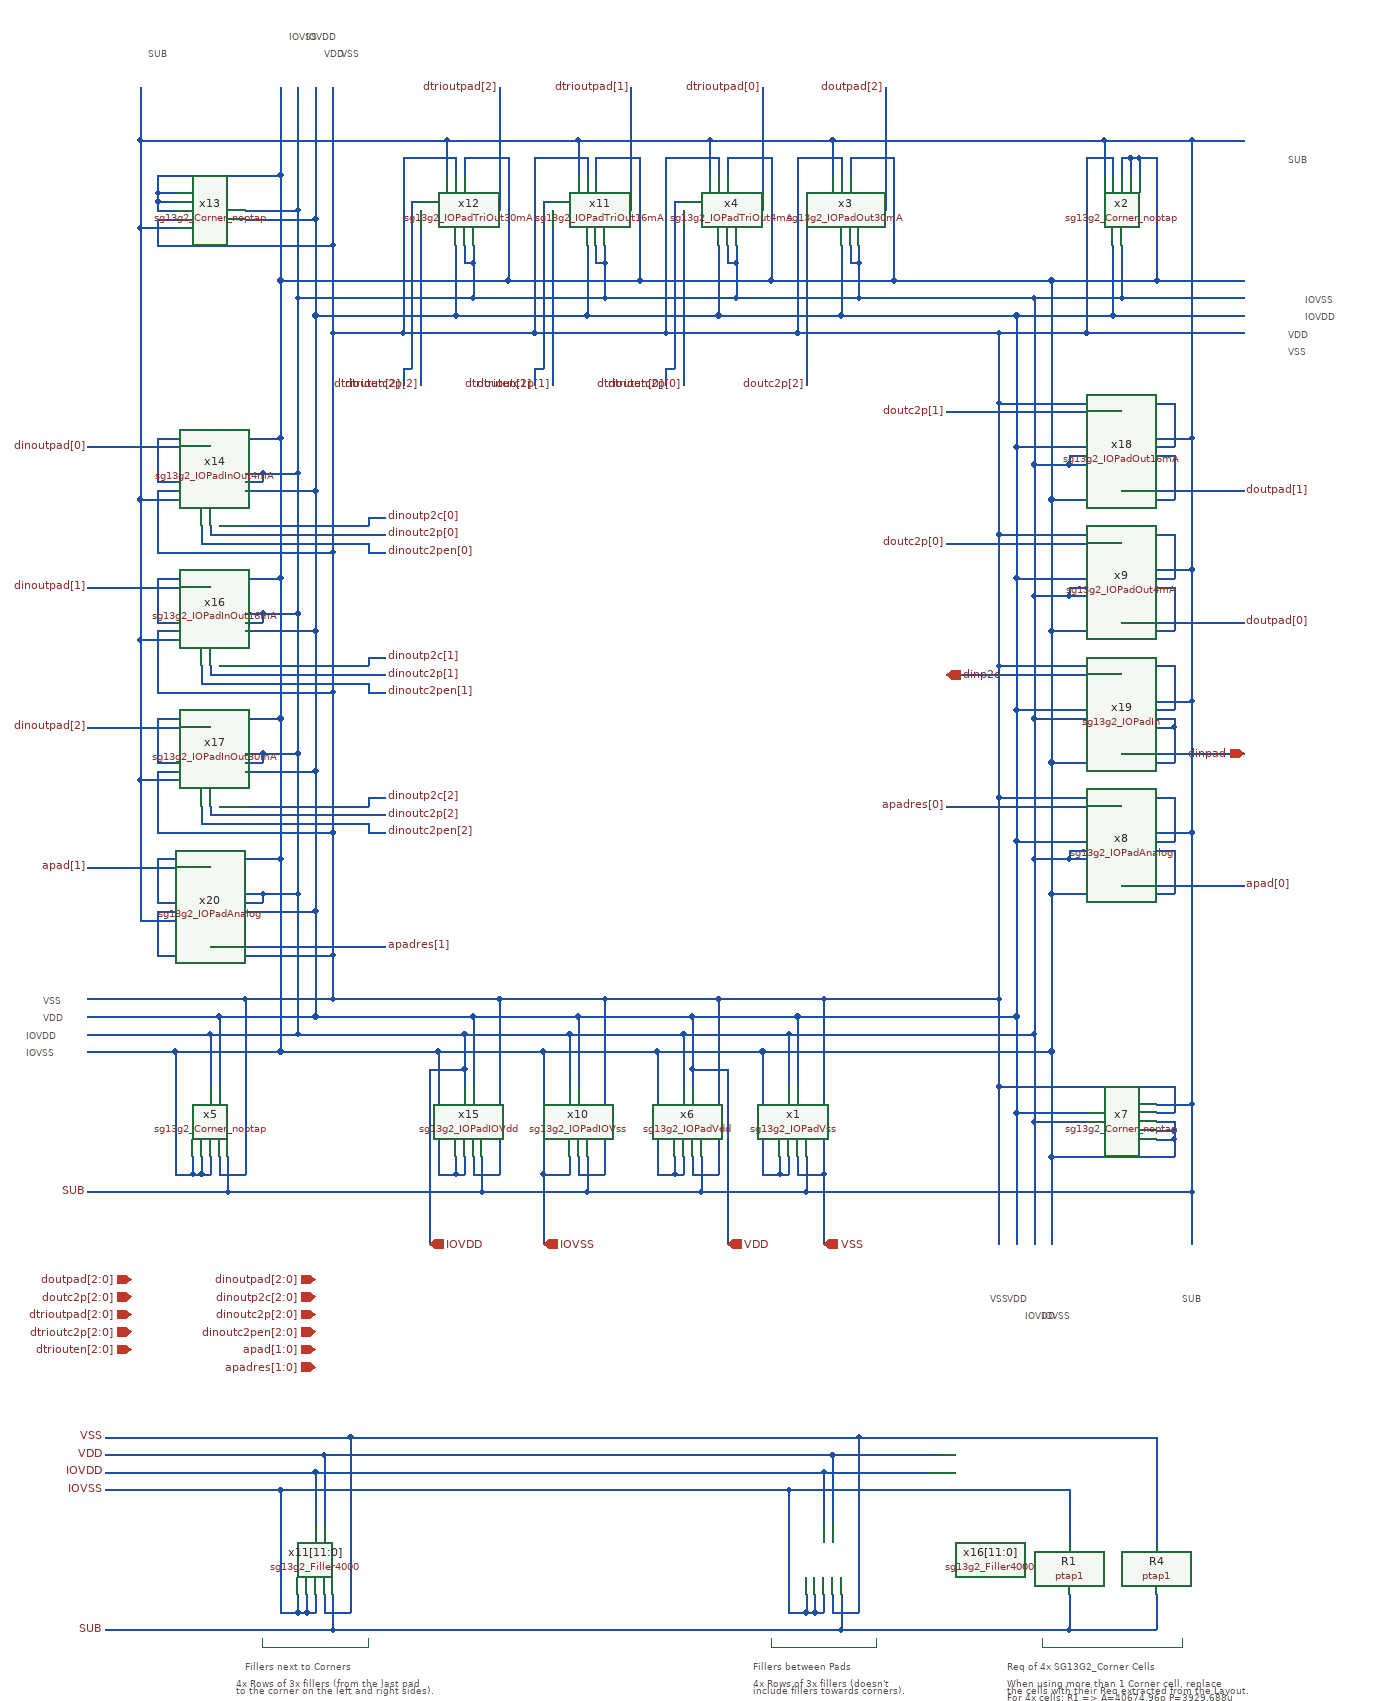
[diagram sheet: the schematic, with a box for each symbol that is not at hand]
v {xschem version=3.4.6 file_version=1.2}
G {}
K {}
V {}
S {}
E {}
L 4 1230 430 1230 440 {}
L 4 1230 440 1390 440 {}
L 4 1390 430 1390 440 {}
L 4 920 430 920 440 {}
L 4 920 440 1040 440 {}
L 4 1040 430 1040 440 {}
L 4 340 430 340 440 {}
L 4 340 440 460 440 {}
L 4 460 430 460 440 {}
T {VSS} 1170 30 3 0 0.3 0.3 {}
T {VDD} 1190 30 3 0 0.3 0.3 {}
T {IOVDD} 1210 50 3 0 0.3 0.3 {}
T {IOVSS} 1230 50 3 0 0.3 0.3 {}
T {SUB} 1390 30 3 0 0.3 0.3 {}
T {Req of 4x SG13G2_Corner Cells} 1190 450 0 0 0.3 0.3 {}
T {When using more than 1 Corner cell, replace
the cells with their Req extracted from the Layout.
For 4x cells: R1 => A=40674.96p P=3929.688u
              R2 => A=52.7736p P=338.816u} 1190 470 0 0 0.2 0.2 {}
T {Fillers between Pads} 900 450 0 0 0.3 0.3 {}
T {4x Rows of 3x fillers (doesn't
include fillers towards corners).} 900 470 0 0 0.2 0.2 {}
T {Fillers next to Corners} 320 450 0 0 0.3 0.3 {}
T {4x Rows of 3x fillers (from the last pad
to the corner on the left and right sides).} 310 470 0 0 0.2 0.2 {}
T {VSS} 1510 -1050 2 0 0.3 0.3 {}
T {VDD} 1510 -1070 2 0 0.3 0.3 {}
T {IOVDD} 1530 -1090 2 0 0.3 0.3 {}
T {IOVSS} 1530 -1110 2 0 0.3 0.3 {}
T {SUB} 1510 -1270 2 0 0.3 0.3 {}
T {VSS} 430 -1390 1 0 0.3 0.3 {}
T {VDD} 410 -1390 1 0 0.3 0.3 {}
T {IOVDD} 390 -1410 1 0 0.3 0.3 {}
T {IOVSS} 370 -1410 1 0 0.3 0.3 {}
T {SUB} 210 -1390 1 0 0.3 0.3 {}
T {VSS} 90 -310 0 0 0.3 0.3 {}
T {VDD} 90 -290 0 0 0.3 0.3 {}
T {IOVDD} 70 -270 0 0 0.3 0.3 {}
T {IOVSS} 70 -250 0 0 0.3 0.3 {}
N 140 -300 320 -300 {lab=VSS}
N 140 -280 290 -280 {lab=VDD}
N 140 -260 280 -260 {lab=IOVDD}
N 140 -240 240 -240 {lab=IOVSS}
N 300 -120 300 -80 {lab=SUB}
N 260 -120 260 -100 {lab=IOVSS}
N 270 -120 270 -100 {lab=IOVSS}
N 260 -100 270 -100 {lab=IOVSS}
N 290 -120 290 -100 {lab=VSS}
N 290 -100 320 -100 {lab=VSS}
N 320 -300 320 -100 {lab=VSS}
N 290 -280 290 -200 {lab=VDD}
N 280 -260 280 -200 {lab=IOVDD}
N 240 -100 260 -100 {lab=IOVSS}
N 240 -240 240 -100 {lab=IOVSS}
N 280 -120 280 -100 {lab=IOVSS}
N 270 -100 280 -100 {lab=IOVSS}
N 580 -120 580 -100 {lab=VSS}
N 580 -100 610 -100 {lab=VSS}
N 610 -300 610 -100 {lab=VSS}
N 580 -280 580 -200 {lab=VDD}
N 570 -220 570 -200 {lab=IOVDD}
N 560 -120 560 -100 {lab=IOVSS}
N 570 -120 570 -100 {lab=IOVSS}
N 560 -100 570 -100 {lab=IOVSS}
N 540 -100 560 -100 {lab=IOVSS}
N 540 -240 540 -100 {lab=IOVSS}
N 700 -120 700 -100 {lab=VSS}
N 700 -100 730 -100 {lab=VSS}
N 730 -300 730 -100 {lab=VSS}
N 700 -280 700 -200 {lab=VDD}
N 690 -260 690 -200 {lab=IOVDD}
N 690 -120 690 -100 {lab=IOVSS}
N 660 -100 690 -100 {lab=IOVSS}
N 660 -240 660 -100 {lab=IOVSS}
N 610 -300 730 -300 {lab=VSS}
N 580 -280 700 -280 {lab=VDD}
N 570 -260 690 -260 {lab=IOVDD}
N 540 -240 660 -240 {lab=IOVSS}
N 910 -240 1240 -240 {lab=IOVSS}
N 980 -300 1180 -300 {lab=VSS}
N 940 -260 1220 -260 {lab=IOVDD}
N 160 200 440 200 {lab=VSS}
N 160 220 410 220 {lab=VDD}
N 160 240 400 240 {lab=IOVDD}
N 160 260 360 260 {lab=IOVSS}
N 160 420 420 420 {lab=SUB}
N 420 380 420 420 {lab=SUB}
N 380 380 380 400 {lab=IOVSS}
N 390 380 390 400 {lab=IOVSS}
N 380 400 390 400 {lab=IOVSS}
N 410 380 410 400 {lab=VSS}
N 410 400 440 400 {lab=VSS}
N 440 200 440 400 {lab=VSS}
N 410 220 410 300 {lab=VDD}
N 400 240 400 300 {lab=IOVDD}
N 360 400 380 400 {lab=IOVSS}
N 360 260 360 400 {lab=IOVSS}
N 400 380 400 400 {lab=IOVSS}
N 390 400 400 400 {lab=IOVSS}
N 440 200 1020 200 {lab=VSS}
N 410 220 990 220 {lab=VDD}
N 400 240 980 240 {lab=IOVDD}
N 360 260 940 260 {lab=IOVSS}
N 960 380 960 400 {lab=IOVSS}
N 970 380 970 400 {lab=IOVSS}
N 960 400 970 400 {lab=IOVSS}
N 990 380 990 400 {lab=VSS}
N 990 400 1020 400 {lab=VSS}
N 1020 200 1020 400 {lab=VSS}
N 990 220 990 300 {lab=VDD}
N 980 240 980 300 {lab=IOVDD}
N 940 400 960 400 {lab=IOVSS}
N 940 260 940 400 {lab=IOVSS}
N 980 380 980 400 {lab=IOVSS}
N 970 400 980 400 {lab=IOVSS}
N 1020 200 1360 200 {lab=VSS}
N 990 220 1110 220 {lab=VDD}
N 980 240 1100 240 {lab=IOVDD}
N 940 260 1260 260 {lab=IOVSS}
N 1000 420 1260 420 {lab=SUB}
N 1000 380 1000 420 {lab=SUB}
N 420 420 1000 420 {lab=SUB}
N 710 -120 710 -80 {lab=SUB}
N 590 -80 710 -80 {lab=SUB}
N 590 -120 590 -80 {lab=SUB}
N 300 -80 590 -80 {lab=SUB}
N 1200 -170 1200 -20 {lab=VDD}
N 1220 -160 1220 -20 {lab=IOVDD}
N 1240 -120 1240 -20 {lab=IOVSS}
N 1360 -180 1400 -180 {lab=SUB}
N 1360 -140 1380 -140 {lab=IOVSS}
N 1360 -150 1380 -150 {lab=IOVSS}
N 1380 -150 1380 -140 {lab=IOVSS}
N 1360 -170 1380 -170 {lab=VSS}
N 1380 -200 1380 -170 {lab=VSS}
N 1180 -200 1380 -200 {lab=VSS}
N 1200 -170 1280 -170 {lab=VDD}
N 1220 -160 1280 -160 {lab=IOVDD}
N 1380 -140 1380 -120 {lab=IOVSS}
N 1240 -120 1380 -120 {lab=IOVSS}
N 1360 -160 1380 -160 {lab=IOVSS}
N 1380 -160 1380 -150 {lab=IOVSS}
N 1180 -300 1180 -200 {lab=VSS}
N 1200 -280 1200 -170 {lab=VDD}
N 1220 -260 1220 -160 {lab=IOVDD}
N 1240 -240 1240 -120 {lab=IOVSS}
N 1120 -520 1320 -520 {lab=apadres[0]}
N 1320 -430 1460 -430 {lab=apad[0]}
N 1360 -470 1380 -470 {lab=IOVSS}
N 1380 -470 1380 -420 {lab=IOVSS}
N 1240 -420 1380 -420 {lab=IOVSS}
N 1240 -420 1240 -240 {lab=IOVSS}
N 1360 -480 1380 -480 {lab=VSS}
N 1380 -530 1380 -480 {lab=VSS}
N 1180 -530 1380 -530 {lab=VSS}
N 1180 -530 1180 -300 {lab=VSS}
N 1260 -460 1280 -460 {lab=IOVDD}
N 1220 -460 1220 -260 {lab=IOVDD}
N 1260 -470 1280 -470 {lab=IOVDD}
N 1260 -470 1260 -460 {lab=IOVDD}
N 1220 -460 1260 -460 {lab=IOVDD}
N 1200 -480 1280 -480 {lab=VDD}
N 1200 -480 1200 -280 {lab=VDD}
N 1120 -670 1320 -670 {lab=dinp2c}
N 1320 -580 1460 -580 {lab=dinpad}
N 1360 -620 1380 -620 {lab=IOVSS}
N 1380 -610 1380 -570 {lab=IOVSS}
N 1240 -570 1380 -570 {lab=IOVSS}
N 1360 -630 1380 -630 {lab=VSS}
N 1380 -680 1380 -630 {lab=VSS}
N 1180 -680 1380 -680 {lab=VSS}
N 1200 -630 1280 -630 {lab=VDD}
N 1240 -570 1240 -420 {lab=IOVSS}
N 1180 -680 1180 -530 {lab=VSS}
N 1200 -630 1200 -480 {lab=VDD}
N 1360 -640 1400 -640 {lab=SUB}
N 1400 -640 1400 -490 {lab=SUB}
N 1360 -490 1400 -490 {lab=SUB}
N 1400 -490 1400 -180 {lab=SUB}
N 1400 -80 1400 -20 {lab=SUB}
N 1260 260 1260 320 {lab=IOVSS}
N 1260 380 1260 420 {lab=SUB}
N 1260 420 1360 420 {lab=SUB}
N 1360 380 1360 420 {lab=SUB}
N 1360 200 1360 320 {lab=VSS}
N 1180 -200 1180 -20 {lab=VSS}
N 1310 -1080 1460 -1080 {lab=VDD}
N 1320 -1100 1460 -1100 {lab=IOVDD}
N 1360 -1120 1460 -1120 {lab=IOVSS}
N 1300 -1280 1300 -1240 {lab=SUB}
N 1340 -1260 1340 -1240 {lab=IOVSS}
N 1330 -1260 1330 -1240 {lab=IOVSS}
N 1330 -1260 1340 -1260 {lab=IOVSS}
N 1310 -1260 1310 -1240 {lab=VSS}
N 1280 -1260 1310 -1260 {lab=VSS}
N 1280 -1260 1280 -1060 {lab=VSS}
N 1310 -1160 1310 -1080 {lab=VDD}
N 1320 -1160 1320 -1100 {lab=IOVDD}
N 1340 -1260 1360 -1260 {lab=IOVSS}
N 1360 -1260 1360 -1120 {lab=IOVSS}
N 1320 -1260 1320 -1240 {lab=IOVSS}
N 1320 -1260 1330 -1260 {lab=IOVSS}
N 1180 -1060 1280 -1060 {lab=VSS}
N 1200 -1080 1310 -1080 {lab=VDD}
N 1220 -1100 1320 -1100 {lab=IOVDD}
N 1240 -1120 1360 -1120 {lab=IOVSS}
N 1400 -1280 1460 -1280 {lab=SUB}
N 1280 -1060 1460 -1060 {lab=VSS}
N 1400 -180 1400 -80 {lab=SUB}
N 1400 -790 1400 -640 {lab=SUB}
N 1300 -1280 1400 -1280 {lab=SUB}
N 1180 -830 1180 -680 {lab=VSS}
N 1220 -620 1220 -460 {lab=IOVDD}
N 1240 -720 1240 -570 {lab=IOVSS}
N 1060 -1120 1240 -1120 {lab=IOVSS}
N 400 -1340 400 -1190 {lab=VDD}
N 380 -1340 380 -1200 {lab=IOVDD}
N 360 -1340 360 -1240 {lab=IOVSS}
N 200 -1180 240 -1180 {lab=SUB}
N 220 -1220 240 -1220 {lab=IOVSS}
N 220 -1210 240 -1210 {lab=IOVSS}
N 220 -1220 220 -1210 {lab=IOVSS}
N 220 -1190 240 -1190 {lab=VSS}
N 220 -1190 220 -1160 {lab=VSS}
N 220 -1160 420 -1160 {lab=VSS}
N 320 -1190 400 -1190 {lab=VDD}
N 320 -1200 380 -1200 {lab=IOVDD}
N 220 -1240 220 -1220 {lab=IOVSS}
N 220 -1240 360 -1240 {lab=IOVSS}
N 220 -1200 240 -1200 {lab=IOVSS}
N 220 -1210 220 -1200 {lab=IOVSS}
N 420 -1340 420 -1160 {lab=VSS}
N 200 -1280 200 -1180 {lab=SUB}
N 360 -460 360 -240 {lab=IOVSS}
N 380 -420 380 -260 {lab=IOVDD}
N 400 -400 400 -280 {lab=VDD}
N 140 -80 300 -80 {lab=SUB}
N 420 -300 610 -300 {lab=VSS}
N 400 -280 580 -280 {lab=VDD}
N 380 -260 570 -260 {lab=IOVDD}
N 360 -240 540 -240 {lab=IOVSS}
N 530 -220 570 -220 {lab=IOVDD}
N 570 -260 570 -220 {lab=IOVDD}
N 530 -220 530 -20 {lab=IOVDD}
N 660 -100 660 -20 {lab=IOVSS}
N 950 -280 1200 -280 {lab=VDD}
N 960 -80 1400 -80 {lab=SUB}
N 830 -120 830 -100 {lab=VSS}
N 830 -100 860 -100 {lab=VSS}
N 860 -300 860 -100 {lab=VSS}
N 830 -220 830 -200 {lab=VDD}
N 810 -120 810 -100 {lab=IOVSS}
N 820 -120 820 -100 {lab=IOVSS}
N 810 -100 820 -100 {lab=IOVSS}
N 790 -100 810 -100 {lab=IOVSS}
N 790 -240 790 -100 {lab=IOVSS}
N 950 -120 950 -100 {lab=VSS}
N 950 -100 980 -100 {lab=VSS}
N 980 -300 980 -100 {lab=VSS}
N 950 -280 950 -200 {lab=VDD}
N 940 -260 940 -200 {lab=IOVDD}
N 940 -120 940 -100 {lab=IOVSS}
N 930 -100 940 -100 {lab=IOVSS}
N 910 -240 910 -100 {lab=IOVSS}
N 960 -120 960 -80 {lab=SUB}
N 840 -120 840 -80 {lab=SUB}
N 820 -260 820 -200 {lab=IOVDD}
N 730 -300 860 -300 {lab=VSS}
N 700 -280 830 -280 {lab=VDD}
N 660 -240 790 -240 {lab=IOVSS}
N 860 -300 980 -300 {lab=VSS}
N 830 -280 950 -280 {lab=VDD}
N 820 -260 940 -260 {lab=IOVDD}
N 790 -240 910 -240 {lab=IOVSS}
N 840 -80 960 -80 {lab=SUB}
N 710 -80 840 -80 {lab=SUB}
N 690 -260 820 -260 {lab=IOVDD}
N 830 -220 870 -220 {lab=VDD}
N 830 -280 830 -220 {lab=VDD}
N 870 -220 870 -20 {lab=VDD}
N 980 -100 980 -20 {lab=VSS}
N 1220 -620 1280 -620 {lab=IOVDD}
N 1220 -760 1220 -620 {lab=IOVDD}
N 1360 -610 1380 -610 {lab=IOVSS}
N 1380 -620 1380 -610 {lab=IOVSS}
N 1120 -820 1320 -820 {lab=doutc2p[0]}
N 1320 -730 1460 -730 {lab=doutpad[0]}
N 1360 -770 1380 -770 {lab=IOVSS}
N 1240 -720 1380 -720 {lab=IOVSS}
N 1360 -780 1380 -780 {lab=VSS}
N 1380 -830 1380 -780 {lab=VSS}
N 1180 -830 1380 -830 {lab=VSS}
N 1360 -790 1400 -790 {lab=SUB}
N 1260 -760 1280 -760 {lab=IOVDD}
N 1380 -770 1380 -720 {lab=IOVSS}
N 1240 -870 1240 -720 {lab=IOVSS}
N 1180 -980 1180 -830 {lab=VSS}
N 1200 -780 1200 -630 {lab=VDD}
N 1400 -940 1400 -790 {lab=SUB}
N 1220 -910 1220 -760 {lab=IOVDD}
N 1120 -970 1320 -970 {lab=doutc2p[1]}
N 1320 -880 1460 -880 {lab=doutpad[1]}
N 1360 -920 1380 -920 {lab=IOVSS}
N 1240 -870 1380 -870 {lab=IOVSS}
N 1360 -930 1380 -930 {lab=VSS}
N 1380 -980 1380 -930 {lab=VSS}
N 1180 -980 1380 -980 {lab=VSS}
N 1360 -940 1400 -940 {lab=SUB}
N 1260 -910 1280 -910 {lab=IOVDD}
N 1380 -920 1380 -870 {lab=IOVSS}
N 1240 -1120 1240 -870 {lab=IOVSS}
N 1180 -1060 1180 -980 {lab=VSS}
N 1200 -930 1200 -780 {lab=VDD}
N 1400 -1280 1400 -940 {lab=SUB}
N 1220 -1100 1220 -910 {lab=IOVDD}
N 1200 -1080 1200 -930 {lab=VDD}
N 1200 -780 1280 -780 {lab=VDD}
N 960 -1200 960 -1000 {lab=doutc2p[2]}
N 1050 -1340 1050 -1200 {lab=doutpad[2]}
N 1010 -1260 1010 -1240 {lab=IOVSS}
N 1010 -1260 1060 -1260 {lab=IOVSS}
N 1060 -1260 1060 -1120 {lab=IOVSS}
N 1000 -1260 1000 -1240 {lab=VSS}
N 950 -1260 1000 -1260 {lab=VSS}
N 950 -1260 950 -1060 {lab=VSS}
N 1020 -1160 1020 -1140 {lab=IOVDD}
N 1010 -1160 1010 -1140 {lab=IOVDD}
N 1010 -1140 1020 -1140 {lab=IOVDD}
N 1020 -1140 1020 -1100 {lab=IOVDD}
N 1000 -1160 1000 -1080 {lab=VDD}
N 990 -1280 990 -1240 {lab=SUB}
N 850 -1280 990 -1280 {lab=SUB}
N 920 -1120 1060 -1120 {lab=IOVSS}
N 880 -1100 1020 -1100 {lab=IOVDD}
N 860 -1080 1000 -1080 {lab=VDD}
N 990 -1280 1300 -1280 {lab=SUB}
N 1020 -1100 1220 -1100 {lab=IOVDD}
N 1000 -1080 1200 -1080 {lab=VDD}
N 950 -1060 1180 -1060 {lab=VSS}
N 700 -1280 850 -1280 {lab=SUB}
N 200 -1340 200 -1280 {lab=SUB}
N 770 -1120 920 -1120 {lab=IOVSS}
N 360 -1240 360 -1120 {lab=IOVSS}
N 730 -1100 880 -1100 {lab=IOVDD}
N 380 -1200 380 -1100 {lab=IOVDD}
N 710 -1080 860 -1080 {lab=VDD}
N 400 -1190 400 -1080 {lab=VDD}
N 650 -1060 800 -1060 {lab=VSS}
N 420 -1160 420 -1060 {lab=VSS}
N 200 -550 200 -390 {lab=SUB}
N 320 -300 420 -300 {lab=VSS}
N 290 -280 400 -280 {lab=VDD}
N 280 -260 380 -260 {lab=IOVDD}
N 240 -240 360 -240 {lab=IOVSS}
N 1260 -770 1280 -770 {lab=IOVDD}
N 1260 -770 1260 -760 {lab=IOVDD}
N 1220 -760 1260 -760 {lab=IOVDD}
N 1260 -920 1280 -920 {lab=IOVDD}
N 1200 -930 1280 -930 {lab=VDD}
N 820 -1200 820 -1000 {lab=dtrioutc2p[0]}
N 910 -1340 910 -1200 {lab=dtrioutpad[0]}
N 870 -1260 870 -1240 {lab=IOVSS}
N 870 -1260 920 -1260 {lab=IOVSS}
N 920 -1260 920 -1120 {lab=IOVSS}
N 860 -1260 860 -1240 {lab=VSS}
N 800 -1260 800 -1060 {lab=VSS}
N 880 -1160 880 -1140 {lab=IOVDD}
N 870 -1160 870 -1140 {lab=IOVDD}
N 870 -1140 880 -1140 {lab=IOVDD}
N 880 -1140 880 -1100 {lab=IOVDD}
N 860 -1160 860 -1080 {lab=VDD}
N 850 -1280 850 -1240 {lab=SUB}
N 800 -1060 950 -1060 {lab=VSS}
N 800 -1260 860 -1260 {lab=VSS}
N 810 -1210 820 -1210 {lab=dtriouten[0]}
N 810 -1210 810 -1020 {lab=dtriouten[0]}
N 800 -1020 810 -1020 {lab=dtriouten[0]}
N 800 -1020 800 -1000 {lab=dtriouten[0]}
N 670 -1200 670 -1000 {lab=dtrioutc2p[1]}
N 760 -1340 760 -1200 {lab=dtrioutpad[1]}
N 720 -1260 720 -1240 {lab=IOVSS}
N 720 -1260 770 -1260 {lab=IOVSS}
N 770 -1260 770 -1120 {lab=IOVSS}
N 710 -1260 710 -1240 {lab=VSS}
N 650 -1260 650 -1060 {lab=VSS}
N 730 -1160 730 -1140 {lab=IOVDD}
N 720 -1160 720 -1140 {lab=IOVDD}
N 720 -1140 730 -1140 {lab=IOVDD}
N 730 -1140 730 -1100 {lab=IOVDD}
N 710 -1160 710 -1080 {lab=VDD}
N 700 -1280 700 -1240 {lab=SUB}
N 650 -1260 710 -1260 {lab=VSS}
N 660 -1210 670 -1210 {lab=dtriouten[1]}
N 660 -1210 660 -1020 {lab=dtriouten[1]}
N 650 -1020 660 -1020 {lab=dtriouten[1]}
N 650 -1020 650 -1000 {lab=dtriouten[1]}
N 620 -1120 770 -1120 {lab=IOVSS}
N 500 -1060 650 -1060 {lab=VSS}
N 580 -1100 730 -1100 {lab=IOVDD}
N 560 -1080 710 -1080 {lab=VDD}
N 550 -1280 700 -1280 {lab=SUB}
N 520 -1200 520 -1000 {lab=dtrioutc2p[2]}
N 610 -1340 610 -1200 {lab=dtrioutpad[2]}
N 570 -1260 570 -1240 {lab=IOVSS}
N 570 -1260 620 -1260 {lab=IOVSS}
N 620 -1260 620 -1120 {lab=IOVSS}
N 560 -1260 560 -1240 {lab=VSS}
N 500 -1260 500 -1060 {lab=VSS}
N 580 -1160 580 -1140 {lab=IOVDD}
N 570 -1160 570 -1140 {lab=IOVDD}
N 570 -1140 580 -1140 {lab=IOVDD}
N 580 -1140 580 -1100 {lab=IOVDD}
N 560 -1160 560 -1080 {lab=VDD}
N 550 -1280 550 -1240 {lab=SUB}
N 500 -1260 560 -1260 {lab=VSS}
N 510 -1210 520 -1210 {lab=dtriouten[2]}
N 510 -1210 510 -1020 {lab=dtriouten[2]}
N 500 -1020 510 -1020 {lab=dtriouten[2]}
N 500 -1020 500 -1000 {lab=dtriouten[2]}
N 360 -1120 620 -1120 {lab=IOVSS}
N 420 -1060 500 -1060 {lab=VSS}
N 380 -1100 580 -1100 {lab=IOVDD}
N 400 -1080 560 -1080 {lab=VDD}
N 200 -1280 550 -1280 {lab=SUB}
N 140 -930 280 -930 {lab=dinoutpad[0]}
N 220 -890 240 -890 {lab=IOVSS}
N 220 -940 220 -890 {lab=IOVSS}
N 220 -940 360 -940 {lab=IOVSS}
N 220 -880 240 -880 {lab=VSS}
N 320 -900 340 -900 {lab=IOVDD}
N 320 -890 340 -890 {lab=IOVDD}
N 340 -900 340 -890 {lab=IOVDD}
N 340 -900 380 -900 {lab=IOVDD}
N 320 -880 400 -880 {lab=VDD}
N 200 -870 240 -870 {lab=SUB}
N 220 -880 220 -810 {lab=VSS}
N 270 -840 270 -820 {lab=dinoutc2pen[0]}
N 270 -820 460 -820 {lab=dinoutc2pen[0]}
N 460 -820 460 -810 {lab=dinoutc2pen[0]}
N 460 -810 480 -810 {lab=dinoutc2pen[0]}
N 360 -1120 360 -940 {lab=IOVSS}
N 420 -350 420 -300 {lab=VSS}
N 380 -1100 380 -900 {lab=IOVDD}
N 400 -1080 400 -880 {lab=VDD}
N 200 -1180 200 -870 {lab=SUB}
N 280 -830 480 -830 {lab=dinoutc2p[0]}
N 280 -840 280 -830 {lab=dinoutc2p[0]}
N 290 -840 460 -840 {lab=dinoutp2c[0]}
N 460 -850 460 -840 {lab=dinoutp2c[0]}
N 460 -850 480 -850 {lab=dinoutp2c[0]}
N 220 -810 420 -810 {lab=VSS}
N 420 -1060 420 -810 {lab=VSS}
N 140 -770 280 -770 {lab=dinoutpad[1]}
N 220 -730 240 -730 {lab=IOVSS}
N 220 -780 220 -730 {lab=IOVSS}
N 220 -780 360 -780 {lab=IOVSS}
N 220 -720 240 -720 {lab=VSS}
N 320 -740 340 -740 {lab=IOVDD}
N 320 -730 340 -730 {lab=IOVDD}
N 340 -740 340 -730 {lab=IOVDD}
N 340 -740 380 -740 {lab=IOVDD}
N 320 -720 400 -720 {lab=VDD}
N 200 -710 240 -710 {lab=SUB}
N 220 -720 220 -650 {lab=VSS}
N 270 -680 270 -660 {lab=dinoutc2pen[1]}
N 270 -660 460 -660 {lab=dinoutc2pen[1]}
N 460 -660 460 -650 {lab=dinoutc2pen[1]}
N 460 -650 480 -650 {lab=dinoutc2pen[1]}
N 280 -670 480 -670 {lab=dinoutc2p[1]}
N 280 -680 280 -670 {lab=dinoutc2p[1]}
N 290 -680 460 -680 {lab=dinoutp2c[1]}
N 460 -690 460 -680 {lab=dinoutp2c[1]}
N 460 -690 480 -690 {lab=dinoutp2c[1]}
N 220 -650 420 -650 {lab=VSS}
N 360 -940 360 -780 {lab=IOVSS}
N 380 -900 380 -740 {lab=IOVDD}
N 400 -880 400 -720 {lab=VDD}
N 200 -870 200 -710 {lab=SUB}
N 420 -810 420 -650 {lab=VSS}
N 140 -610 280 -610 {lab=dinoutpad[2]}
N 220 -570 240 -570 {lab=IOVSS}
N 220 -620 220 -570 {lab=IOVSS}
N 220 -620 360 -620 {lab=IOVSS}
N 220 -560 240 -560 {lab=VSS}
N 320 -580 340 -580 {lab=IOVDD}
N 320 -570 340 -570 {lab=IOVDD}
N 340 -580 340 -570 {lab=IOVDD}
N 340 -580 380 -580 {lab=IOVDD}
N 320 -560 400 -560 {lab=VDD}
N 200 -550 240 -550 {lab=SUB}
N 220 -560 220 -490 {lab=VSS}
N 270 -520 270 -500 {lab=dinoutc2pen[2]}
N 270 -500 460 -500 {lab=dinoutc2pen[2]}
N 460 -500 460 -490 {lab=dinoutc2pen[2]}
N 460 -490 480 -490 {lab=dinoutc2pen[2]}
N 280 -510 480 -510 {lab=dinoutc2p[2]}
N 280 -520 280 -510 {lab=dinoutc2p[2]}
N 290 -520 460 -520 {lab=dinoutp2c[2]}
N 460 -530 460 -520 {lab=dinoutp2c[2]}
N 460 -530 480 -530 {lab=dinoutp2c[2]}
N 220 -490 420 -490 {lab=VSS}
N 360 -780 360 -620 {lab=IOVSS}
N 380 -740 380 -580 {lab=IOVDD}
N 400 -720 400 -560 {lab=VDD}
N 200 -710 200 -550 {lab=SUB}
N 420 -650 420 -490 {lab=VSS}
N 280 -360 480 -360 {lab=apadres[1]}
N 140 -450 280 -450 {lab=apad[1]}
N 220 -410 240 -410 {lab=IOVSS}
N 220 -460 220 -410 {lab=IOVSS}
N 220 -460 360 -460 {lab=IOVSS}
N 220 -400 240 -400 {lab=VSS}
N 220 -400 220 -350 {lab=VSS}
N 220 -350 420 -350 {lab=VSS}
N 320 -420 340 -420 {lab=IOVDD}
N 320 -410 340 -410 {lab=IOVDD}
N 340 -420 340 -410 {lab=IOVDD}
N 340 -420 380 -420 {lab=IOVDD}
N 320 -400 400 -400 {lab=VDD}
N 200 -390 240 -390 {lab=SUB}
N 360 -620 360 -460 {lab=IOVSS}
N 420 -490 420 -350 {lab=VSS}
N 380 -580 380 -420 {lab=IOVDD}
N 400 -560 400 -400 {lab=VDD}
N 930 -120 930 -100 {lab=IOVSS}
N 910 -100 930 -100 {lab=IOVSS}
N 1260 -920 1260 -910 {lab=IOVDD}
N 1220 -910 1260 -910 {lab=IOVDD}
C {sg13g2_Corner_noptap.sym} 290 -160 0 0 {name=x5}
C {sg13g2_IOPadIOVss.sym} 700 -160 0 0 {name=x10}
C {sg13g2_Filler4000.sym} 400 340 0 0 {name=x11[11:0]}
C {sg13g2_IOPadIOVdd.sym} 580 -160 0 0 {name=x15}
C {sg13g2_Filler4000.sym} 980 340 0 0 {name=x16[11:0]}
C {iopin.sym} 980 -20 3 1 {name=p1 lab=VSS}
C {iopin.sym} 870 -20 3 1 {name=p2 lab=VDD}
C {iopin.sym} 530 -20 3 1 {name=p3 lab=IOVDD}
C {iopin.sym} 660 -20 3 1 {name=p4 lab=IOVSS}
C {lab_pin.sym} 160 200 0 0 {name=p6 sig_type=std_logic lab=VSS}
C {lab_pin.sym} 160 220 0 0 {name=p7 sig_type=std_logic lab=VDD}
C {lab_pin.sym} 160 240 0 0 {name=p8 sig_type=std_logic lab=IOVDD}
C {lab_pin.sym} 160 260 0 0 {name=p9 sig_type=std_logic lab=IOVSS}
C {lab_pin.sym} 160 420 0 0 {name=p10 sig_type=std_logic lab=SUB}
C {iopin.sym} 190 20 2 0 {name=p11 lab=doutpad[2:0]}
C {sg13g2_Corner_noptap.sym} 1320 -170 3 0 {name=x7}
C {sg13g2_IOPadAnalog.sym} 1320 -480 3 0 {name=x8}
C {sg13g2_IOPadIn.sym} 1320 -630 3 0 {name=x19}
C {noconn.sym} 1180 -20 3 0 {name=l19}
C {noconn.sym} 1200 -20 3 0 {name=l20}
C {noconn.sym} 1220 -20 3 0 {name=l21}
C {noconn.sym} 1240 -20 3 0 {name=l22}
C {noconn.sym} 1400 -20 3 0 {name=l23}
C {lab_pin.sym} 140 -80 0 0 {name=p5 sig_type=std_logic lab=SUB}
C {sg13g2_pr/ptap1.sym} 1360 350 0 0 {name=R4
model=ptap1
spiceprefix=X
w=7.27e-6
l=7.27e-6
lvs_format="tcleval(@name @pinlist @model A=52.7736p P=338.816u )"
}
C {sg13g2_pr/ptap1.sym} 1260 350 0 0 {name=R1
model=ptap1
spiceprefix=X
w=201.69e-6
l=201.69e-6
lvs_format="tcleval(@name @pinlist @model A=40674.96p P=3929.688u )"
}
C {sg13g2_Corner_noptap.sym} 1310 -1200 2 0 {name=x2}
C {noconn.sym} 1460 -1060 2 0 {name=l5}
C {noconn.sym} 1460 -1080 2 0 {name=l6}
C {noconn.sym} 1460 -1100 2 0 {name=l7}
C {noconn.sym} 1460 -1120 2 0 {name=l8}
C {noconn.sym} 1460 -1280 2 0 {name=l9}
C {sg13g2_Corner_noptap.sym} 280 -1190 1 0 {name=x13}
C {noconn.sym} 420 -1340 1 0 {name=l14}
C {noconn.sym} 400 -1340 1 0 {name=l15}
C {noconn.sym} 380 -1340 1 0 {name=l16}
C {noconn.sym} 360 -1340 1 0 {name=l17}
C {noconn.sym} 200 -1340 1 0 {name=l18}
C {noconn.sym} 140 -300 0 0 {name=l24}
C {noconn.sym} 140 -280 0 0 {name=l25}
C {noconn.sym} 140 -260 0 0 {name=l26}
C {noconn.sym} 140 -240 0 0 {name=l27}
C {sg13g2_IOPadVss.sym} 950 -160 0 0 {name=x1}
C {sg13g2_IOPadVdd.sym} 830 -160 0 0 {name=x6}
C {sg13g2_IOPadOut4mA.sym} 1320 -770 3 1 {name=x9}
C {sg13g2_IOPadOut16mA.sym} 1320 -920 3 1 {name=x18}
C {iopin.sym} 1460 -580 0 0 {name=p18 lab=dinpad}
C {iopin.sym} 1120 -670 0 1 {name=p19 lab=dinp2c}
C {sg13g2_IOPadOut30mA.sym} 1010 -1200 2 1 {name=x3}
C {sg13g2_IOPadTriOut4mA.sym} 870 -1200 2 1 {name=x4}
C {sg13g2_IOPadTriOut16mA.sym} 720 -1200 2 1 {name=x11}
C {sg13g2_IOPadTriOut30mA.sym} 570 -1200 2 1 {name=x12}
C {sg13g2_IOPadInOut4mA.sym} 280 -890 1 1 {name=x14}
C {iopin.sym} 190 40 2 0 {name=p35 lab=doutc2p[2:0]}
C {lab_pin.sym} 1460 -730 0 1 {name=p36 sig_type=std_logic lab=doutpad[0]}
C {lab_pin.sym} 1120 -820 0 0 {name=p37 sig_type=std_logic lab=doutc2p[0]}
C {lab_pin.sym} 1460 -880 0 1 {name=p20 sig_type=std_logic lab=doutpad[1]}
C {lab_pin.sym} 1120 -970 0 0 {name=p21 sig_type=std_logic lab=doutc2p[1]}
C {lab_pin.sym} 1050 -1340 3 1 {name=p22 sig_type=std_logic lab=doutpad[2]}
C {lab_pin.sym} 960 -1000 3 0 {name=p23 sig_type=std_logic lab=doutc2p[2]}
C {lab_pin.sym} 910 -1340 3 1 {name=p12 sig_type=std_logic lab=dtrioutpad[0]}
C {lab_pin.sym} 820 -1000 3 0 {name=p13 sig_type=std_logic lab=dtrioutc2p[0]}
C {lab_pin.sym} 800 -1000 3 0 {name=p24 sig_type=std_logic lab=dtriouten[0]}
C {lab_pin.sym} 760 -1340 3 1 {name=p25 sig_type=std_logic lab=dtrioutpad[1]}
C {lab_pin.sym} 670 -1000 3 0 {name=p26 sig_type=std_logic lab=dtrioutc2p[1]}
C {lab_pin.sym} 650 -1000 3 0 {name=p27 sig_type=std_logic lab=dtriouten[1]}
C {lab_pin.sym} 610 -1340 3 1 {name=p28 sig_type=std_logic lab=dtrioutpad[2]}
C {lab_pin.sym} 520 -1000 3 0 {name=p29 sig_type=std_logic lab=dtrioutc2p[2]}
C {lab_pin.sym} 500 -1000 3 0 {name=p30 sig_type=std_logic lab=dtriouten[2]}
C {iopin.sym} 190 60 2 0 {name=p31 lab=dtrioutpad[2:0]}
C {iopin.sym} 190 80 2 0 {name=p32 lab=dtrioutc2p[2:0]}
C {iopin.sym} 190 100 2 0 {name=p38 lab=dtriouten[2:0]}
C {lab_pin.sym} 140 -930 0 0 {name=p39 sig_type=std_logic lab=dinoutpad[0]}
C {lab_pin.sym} 480 -850 0 1 {name=p15 sig_type=std_logic lab=dinoutp2c[0]}
C {lab_pin.sym} 480 -830 0 1 {name=p14 sig_type=std_logic lab=dinoutc2p[0]}
C {lab_pin.sym} 480 -810 0 1 {name=p34 sig_type=std_logic lab=dinoutc2pen[0]}
C {sg13g2_IOPadInOut16mA.sym} 280 -730 1 1 {name=x16}
C {lab_pin.sym} 140 -770 0 0 {name=p33 sig_type=std_logic lab=dinoutpad[1]}
C {lab_pin.sym} 480 -690 0 1 {name=p40 sig_type=std_logic lab=dinoutp2c[1]}
C {lab_pin.sym} 480 -670 0 1 {name=p41 sig_type=std_logic lab=dinoutc2p[1]}
C {lab_pin.sym} 480 -650 0 1 {name=p42 sig_type=std_logic lab=dinoutc2pen[1]}
C {sg13g2_IOPadInOut30mA.sym} 280 -570 1 1 {name=x17}
C {lab_pin.sym} 140 -610 0 0 {name=p43 sig_type=std_logic lab=dinoutpad[2]}
C {lab_pin.sym} 480 -530 0 1 {name=p44 sig_type=std_logic lab=dinoutp2c[2]}
C {lab_pin.sym} 480 -510 0 1 {name=p45 sig_type=std_logic lab=dinoutc2p[2]}
C {lab_pin.sym} 480 -490 0 1 {name=p46 sig_type=std_logic lab=dinoutc2pen[2]}
C {iopin.sym} 400 20 2 0 {name=p47 lab=dinoutpad[2:0]}
C {iopin.sym} 400 40 2 0 {name=p48 lab=dinoutp2c[2:0]}
C {iopin.sym} 400 60 2 0 {name=p49 lab=dinoutc2p[2:0]}
C {iopin.sym} 400 80 2 0 {name=p50 lab=dinoutc2pen[2:0]}
C {lab_pin.sym} 1460 -430 0 1 {name=p51 sig_type=std_logic lab=apad[0]}
C {lab_pin.sym} 1120 -520 0 0 {name=p52 sig_type=std_logic lab=apadres[0]}
C {sg13g2_IOPadAnalog.sym} 280 -400 1 0 {name=x20}
C {lab_pin.sym} 140 -450 2 1 {name=p16 sig_type=std_logic lab=apad[1]}
C {lab_pin.sym} 480 -360 2 0 {name=p17 sig_type=std_logic lab=apadres[1]}
C {iopin.sym} 400 100 2 0 {name=p53 lab=apad[1:0]}
C {iopin.sym} 400 120 2 0 {name=p54 lab=apadres[1:0]}
